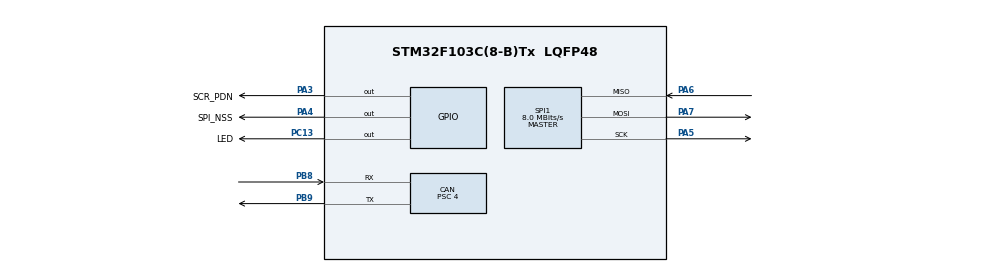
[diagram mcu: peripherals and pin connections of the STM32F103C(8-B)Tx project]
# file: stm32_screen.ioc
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CAN.BS2=CAN_BS2_6TQ
CAN.CalculateBaudRate=1000000
CAN.CalculateTimeBit=1000.00
CAN.CalculateTimeQuantum=125.0
CAN.Prescaler=4
Mcu.Family=STM32F1
Mcu.Name=STM32F103C(8-B)Tx
Mcu.Package=LQFP48
NVIC.PriorityGroup=NVIC_PRIORITYGROUP_4
PA13.Mode=Serial_Wire
PA13.Signal=SYS_JTMS-SWDIO
PA14.Mode=Serial_Wire
PA14.Signal=SYS_JTCK-SWCLK
PA3.GPIO_Label=SCR_PDN
PA3.GPIO_PuPd=GPIO_NOPULL
PA3.Signal=GPIO_Output
PA4.GPIO_Label=SPI_NSS
PA4.GPIO_PuPd=GPIO_PULLUP
PA4.GPIO_Speed=GPIO_SPEED_FREQ_HIGH
PA4.PinState=GPIO_PIN_SET
PA4.Signal=GPIO_Output
PA5.Mode=Full_Duplex_Master
PA5.Signal=SPI1_SCK
PA6.Mode=Full_Duplex_Master
PA6.Signal=SPI1_MISO
PA7.Mode=Full_Duplex_Master
PA7.Signal=SPI1_MOSI
PB8.Mode=CAN_Activate
PB8.Signal=CAN_RX
PB9.Mode=CAN_Activate
PB9.Signal=CAN_TX
PC13-TAMPER-RTC.GPIO_Label=LED
PC13-TAMPER-RTC.Signal=GPIO_Output
PC14-OSC32_IN.Mode=LSE-External-Oscillator
PC14-OSC32_IN.Signal=RCC_OSC32_IN
PC15-OSC32_OUT.Mode=LSE-External-Oscillator
PC15-OSC32_OUT.Signal=RCC_OSC32_OUT
PD0-OSC_IN.Mode=HSE-External-Oscillator
PD0-OSC_IN.Signal=RCC_OSC_IN
PD1-OSC_OUT.Mode=HSE-External-Oscillator
PD1-OSC_OUT.Signal=RCC_OSC_OUT
ProjectManager.HeapSize=0x200
ProjectManager.StackSize=0x400
ProjectManager.TargetToolchain=Other Toolchains (GPDSC)
RCC.AHBFreq_Value=64000000
RCC.APB1CLKDivider=RCC_HCLK_DIV2
RCC.APB1Freq_Value=32000000
RCC.APB1TimFreq_Value=64000000
RCC.APB2Freq_Value=64000000
RCC.APB2TimFreq_Value=64000000
RCC.HCLKFreq_Value=64000000
RCC.PLLMUL=RCC_PLL_MUL8
RCC.PLLSourceVirtual=RCC_PLLSOURCE_HSE
RCC.SYSCLKFreq_VALUE=64000000
RCC.SYSCLKSource=RCC_SYSCLKSOURCE_PLLCLK
RCC.USBFreq_Value=42666666.666666664
RCC.USBPrescaler=RCC_USBCLKSOURCE_PLL_DIV1_5
SPI1.BaudRatePrescaler=SPI_BAUDRATEPRESCALER_8
SPI1.CLKPhase=SPI_PHASE_1EDGE
SPI1.CalculateBaudRate=8.0 MBits/s
SPI1.Direction=SPI_DIRECTION_2LINES
SPI1.Mode=SPI_MODE_MASTER
SPI1.VirtualType=VM_MASTER
board=custom

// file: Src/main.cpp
/* USER CODE BEGIN Header */
/**
 ******************************************************************************
 * @file           : main.c
 * @brief          : Main program body
 ******************************************************************************
 * @attention
 *
 * <h2><center>&copy; Copyright (c) 2020 STMicroelectronics.
 * All rights reserved.</center></h2>
 *
 * This software component is licensed by ST under BSD 3-Clause license,
 * the "License"; You may not use this file except in compliance with the
 * License. You may obtain a copy of the License at:
 *                        opensource.org/licenses/BSD-3-Clause
 *
 ******************************************************************************
 */
/* USER CODE END Header */
#include "main.h" // NOLINT build/include_subdir
#include "can.h" // NOLINT build/include_subdir
#include "gpio.h" // NOLINT build/include_subdir
#include "spi.h" // NOLINT build/include_subdir

/* USER CODE BEGIN Includes */
#include "FT_NHD_43RTP_SHIELD.h" // NOLINT build/include_subdir
#include "screen.h" // NOLINT build/include_subdir
/* USER CODE END Includes */

/* USER CODE BEGIN PD */
extern SPI_HandleTypeDef hspi1;
/* USER CODE END PD */

void SystemClock_Config(void);

/* USER CODE BEGIN 0 */
FT800IMPL_SPI SCR;
/* USER CODE END 0 */

uint32_t chipid = 0;
int main(void) {
    /* MCU
     * Configuration--------------------------------------------------------*/

    /* Reset of all peripherals, Initializes the Flash interface and the
     * Systick. */
    HAL_Init();

    /* Configure the system clock */
    SystemClock_Config();

    /* Initialize all configured peripherals */
    MX_GPIO_Init();
    MX_CAN_Init();
    MX_SPI1_Init();

    // General Setup Code
    HAL_GPIO_WritePin(LED_GPIO_Port, LED_Pin, GPIO_PIN_SET);

    SCR = FT800IMPL_SPI(GPIO_PIN_4, GPIOA, SCR_PDN_Pin, SCR_PDN_GPIO_Port);
    HAL_Delay(100);
    SCR.Init(FT_DISPLAY_RESOLUTION, 0); // configure the display to the WQVGA
    HAL_Delay(100);
    chipid = SCR.Read32(FT_ROM_CHIPID);

    if (FT800_CHIPID == chipid) {
        uint8_t counter = 0;
        uint8_t max = 3;
        while (counter++ < max) {
            for (uint8_t i = 0; i < 4; i++) {
                HAL_GPIO_TogglePin(LED_GPIO_Port, LED_Pin);
                HAL_Delay(100);
            }
            HAL_Delay(200);
        }
    } else if (0 == chipid) {
        while (0 == chipid) {
            SCR.Init(FT_DISPLAY_RESOLUTION,
                     0); // configure the display to the WQVGA
            HAL_Delay(100);
            chipid = SCR.Read32(FT_ROM_CHIPID);
            for (uint8_t i = 0; i < 8; i++) {
                HAL_GPIO_TogglePin(LED_GPIO_Port, LED_Pin);
                HAL_Delay(150);
            }
            HAL_Delay(500);
        }
    }

    /* Set the Display & audio pins */
    SCR.SetDisplayEnablePin(FT_DISPENABLE_PIN);
    SCR.SetAudioEnablePin(FT_AUDIOENABLE_PIN);

    // turn the screen on and the amplifier off
    SCR.DisplayOn();
    SCR.AudioOff();

    // infinite loop
    while (1) {
        HAL_GPIO_TogglePin(LED_GPIO_Port, LED_Pin);
        HAL_Delay(100);

        SCR.DLStart();
        main_display();
        SCR.DLEnd();
        SCR.Finish();
    }
}

void SystemClock_Config(void) {
    RCC_OscInitTypeDef RCC_OscInitStruct = {0};
    RCC_ClkInitTypeDef RCC_ClkInitStruct = {0};

    /** Initializes the RCC Oscillators according to the specified parameters
     * in the RCC_OscInitTypeDef structure.
     */
    RCC_OscInitStruct.OscillatorType = RCC_OSCILLATORTYPE_HSE;
    RCC_OscInitStruct.HSEState = RCC_HSE_ON;
    RCC_OscInitStruct.HSEPredivValue = RCC_HSE_PREDIV_DIV1;
    RCC_OscInitStruct.HSIState = RCC_HSI_ON;
    RCC_OscInitStruct.PLL.PLLState = RCC_PLL_ON;
    RCC_OscInitStruct.PLL.PLLSource = RCC_PLLSOURCE_HSE;
    RCC_OscInitStruct.PLL.PLLMUL = RCC_PLL_MUL8;
    if (HAL_RCC_OscConfig(&RCC_OscInitStruct) != HAL_OK) {
        Error_Handler();
    }
    /** Initializes the CPU, AHB and APB buses clocks
     */
    RCC_ClkInitStruct.ClockType = RCC_CLOCKTYPE_HCLK | RCC_CLOCKTYPE_SYSCLK |
                                  RCC_CLOCKTYPE_PCLK1 | RCC_CLOCKTYPE_PCLK2;
    RCC_ClkInitStruct.SYSCLKSource = RCC_SYSCLKSOURCE_PLLCLK;
    RCC_ClkInitStruct.AHBCLKDivider = RCC_SYSCLK_DIV1;
    RCC_ClkInitStruct.APB1CLKDivider = RCC_HCLK_DIV8;
    RCC_ClkInitStruct.APB2CLKDivider = RCC_HCLK_DIV1;

    if (HAL_RCC_ClockConfig(&RCC_ClkInitStruct, FLASH_LATENCY_2) != HAL_OK) {
        Error_Handler();
    }
}

void Error_Handler(void) {
    /* USER CODE BEGIN Error_Handler_Debug */
    /* User can add his own implementation to report the HAL error return state
     */
    __disable_irq();
    while (1) {
    }
    /* USER CODE END Error_Handler_Debug */
}

#ifdef USE_FULL_ASSERT
/**
 * @brief  Reports the name of the source file and the source line number
 *         where the assert_param error has occurred.
 * @param  file: pointer to the source file name
 * @param  line: assert_param error line source number
 * @retval None
 */
void assert_failed(uint8_t *file, uint32_t line) {
    /* USER CODE BEGIN 6 */
    /* User can add his own implementation to report the file name and line
       number, ex: printf("Wrong parameters value: file %s on line %d\r\n",
       file, line) */
    /* USER CODE END 6 */
}
#endif /* USE_FULL_ASSERT */

/************************ (C) COPYRIGHT STMicroelectronics *****END OF FILE****/
